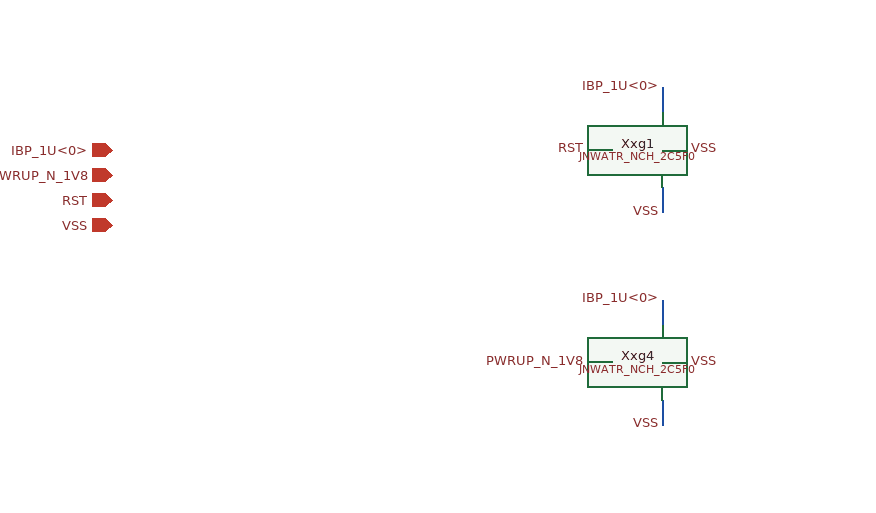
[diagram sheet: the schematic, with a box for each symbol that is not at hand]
v {xschem version=3.0.0 file_version=1.2 }
G {}
K {}
V {}
S {}
E {}
C {devices/iopin.sym} 0 0 0 0 {name=p0 lab=IBP_1U<0>}
C {devices/iopin.sym} 0 20 0 0 {name=p1 lab=PWRUP_N_1V8}
C {devices/iopin.sym} 0 40 0 0 {name=p2 lab=RST}
C {devices/iopin.sym} 0 60 0 0 {name=p3 lab=VSS}
C {JNW_ATR_SKY130A/JNWATR_NCH_2C5F0.sym} 400 0 0 0 {name=Xxg1}
N 440.0 -50.0 440.0 -30.0 {lab=IBP_1U<0>}
C {devices/lab_pin.sym} 440.0 -50.0 3 0 {name=l0 sig_type=std_logic lab=IBP_1U<0> }
N 380.0 0.0 400.0 0.0 {lab=RST}
C {devices/lab_pin.sym} 380.0 0.0 0 0 {name=l1 sig_type=std_logic lab=RST }
N 440.0 50.0 440.0 30.0 {lab=VSS}
C {devices/lab_pin.sym} 440.0 50.0 1 0 {name=l2 sig_type=std_logic lab=VSS }
N 460.0 0.0 440.0 0.0 {lab=VSS}
C {devices/lab_pin.sym} 460.0 0.0 2 0 {name=l3 sig_type=std_logic lab=VSS }
C {JNW_ATR_SKY130A/JNWATR_NCH_2C5F0.sym} 400 170.0 0 0 {name=Xxg4}
N 440.0 120.0 440.0 140.0 {lab=IBP_1U<0>}
C {devices/lab_pin.sym} 440.0 120.0 3 0 {name=l4 sig_type=std_logic lab=IBP_1U<0> }
N 380.0 170.0 400.0 170.0 {lab=PWRUP_N_1V8}
C {devices/lab_pin.sym} 380.0 170.0 0 0 {name=l5 sig_type=std_logic lab=PWRUP_N_1V8 }
N 440.0 220.0 440.0 200.0 {lab=VSS}
C {devices/lab_pin.sym} 440.0 220.0 1 0 {name=l6 sig_type=std_logic lab=VSS }
N 460.0 170.0 440.0 170.0 {lab=VSS}
C {devices/lab_pin.sym} 460.0 170.0 2 0 {name=l7 sig_type=std_logic lab=VSS }
